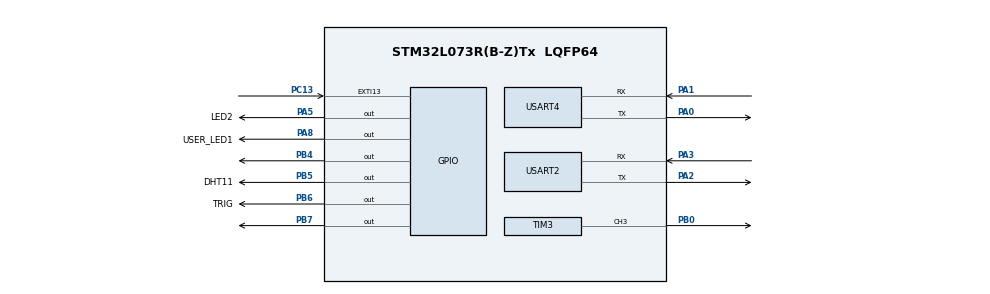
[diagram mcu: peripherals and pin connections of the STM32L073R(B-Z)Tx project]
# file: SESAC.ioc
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Mcu.Family=STM32L0
Mcu.Name=STM32L073R(B-Z)Tx
Mcu.Package=LQFP64
NVIC.EXTI4_15_IRQn=true\:0\:0\:false\:false\:true\:true\:true\:true
NVIC.TIM7_IRQn=true\:0\:0\:false\:false\:true\:true\:true\:true
NVIC.USART2_IRQn=true\:0\:0\:false\:false\:true\:true\:true\:true
NVIC.USART4_5_IRQn=true\:0\:0\:false\:false\:true\:true\:true\:true
PA0.Mode=Asynchronous
PA0.Signal=USART4_TX
PA1.Mode=Asynchronous
PA1.Signal=USART4_RX
PA13.GPIO_Label=TMS
PA13.Mode=Serial_Wire
PA13.Signal=SYS_SWDIO
PA14.GPIO_Label=TCK
PA14.Mode=Serial_Wire
PA14.Signal=SYS_SWCLK
PA2.Mode=Asynchronous
PA2.Signal=USART2_TX
PA3.Mode=Asynchronous
PA3.Signal=USART2_RX
PA5.GPIO_Label=LED2
PA5.Signal=GPIO_Output
PA8.GPIO_Label=USER_LED1
PA8.Signal=GPIO_Output
PB0.Signal=S_TIM3_CH3
PB4.Signal=GPIO_Output
PB5.GPIO_Label=DHT11
PB5.GPIO_Speed=GPIO_SPEED_FREQ_VERY_HIGH
PB5.Signal=GPIO_Output
PB6.GPIO_Label=TRIG
PB6.Signal=GPIO_Output
PB7.Signal=GPIO_Output
PC13.GPIO_ModeDefaultEXTI=GPIO_MODE_IT_FALLING
PC13.GPIO_PuPd=GPIO_PULLUP
PC13.Signal=GPXTI13
PC14-OSC32_IN.Mode=LSE-External-Oscillator
PC14-OSC32_IN.Signal=RCC_OSC32_IN
PC15-OSC32_OUT.Mode=LSE-External-Oscillator
PC15-OSC32_OUT.Signal=RCC_OSC32_OUT
PH0-OSC_IN.GPIO_Label=MCO
PH0-OSC_IN.Mode=HSE-External-Clock-Source
PH0-OSC_IN.Signal=RCC_OSC_IN
ProjectManager.HeapSize=0x200
ProjectManager.StackSize=0x400
ProjectManager.TargetToolchain=MDK-ARM V5.32
RCC.AHBFreq_Value=2097000
RCC.APB1Freq_Value=2097000
RCC.APB1TimFreq_Value=2097000
RCC.APB2Freq_Value=2097000
RCC.APB2TimFreq_Value=2097000
RCC.HSE_VALUE=8000000
RCC.HSI16_VALUE=16000000
RCC.HSI48_VALUE=48000000
RCC.HSI_VALUE=16000000
RCC.MSI_VALUE=2097000
RCC.SYSCLKFreq_VALUE=2097000
RCC.VCOOutputFreq_Value=48000000
SH.S_TIM3_CH3.0=TIM3_CH3,PWM Generation3 CH3
TIM3.Channel-PWM\ Generation3\ CH3=TIM_CHANNEL_3
TIM3.Period=1000-1
TIM3.Prescaler=8-1
USART2.VirtualMode-Asynchronous=VM_ASYNC
USART4.VirtualMode-Asynchronous=VM_ASYNC
VP_TIM7_VS_ClockSourceINT.Mode=Enable_Timer
board=NUCLEO-L073RZ

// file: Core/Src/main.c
#include "main.h"

TIM_HandleTypeDef htim3;
TIM_HandleTypeDef htim7;

UART_HandleTypeDef huart2;
UART_HandleTypeDef huart4;

/* USER CODE BEGIN PV */
uint8_t my_fault = 0;        // ? ??: 0 ??, 1 ??
uint8_t peer_fault = 0;      // ?? Fault ??
uint8_t peer_near = 0;  //distance

uint8_t txByte = 0x00;       // ?? ?? ???
uint8_t rxByte = 0x00;       // ????? ?? ???

uint32_t lastBtnTick = 0;    // ?????

uint8_t is_braking = 0;
uint8_t lastBothFault = 0;

static uint8_t brakeDone = 0;   // 0?? ?? ???? ??, 1?? ???? ?? ??
static uint8_t checkDist = 0;
/* USER CODE END PV */

void SystemClock_Config(void);
static void MX_GPIO_Init(void);
static void MX_TIM7_Init(void);
static void MX_TIM3_Init(void);
static void MX_USART2_UART_Init(void);
static void MX_USART4_UART_Init(void);

/* USER CODE BEGIN 0 */

static void UpdateFaultLeds(void)
{
  static uint32_t lastBlinkTick = 0;
  static uint8_t  blinkState = 0;

  // (1) ? ? Fault?: ?? 1? ??, ?? OFF
  if (my_fault && peer_fault)
  {
    HAL_GPIO_WritePin(GPIOB, GPIO_PIN_7, GPIO_PIN_RESET); // GREEN OFF

    if (HAL_GetTick() - lastBlinkTick >= 1000)   // 1??? ??
    {
      lastBlinkTick = HAL_GetTick();
      blinkState ^= 1;
    }

		HAL_GPIO_WritePin(GPIOA, USER_LED1_Pin,
													blinkState ? GPIO_PIN_SET : GPIO_PIN_RESET);
    return;
  }

  // (2) ? ?: ?? ?? ??(?? ???? ??? ?? ???? ? ??)
  blinkState = 0;
  lastBlinkTick = HAL_GetTick();

  // ?? OFF
  HAL_GPIO_WritePin(GPIOB, GPIO_PIN_7, GPIO_PIN_RESET);
  HAL_GPIO_WritePin(GPIOA, USER_LED1_Pin, GPIO_PIN_RESET);

  // (3) ? fault? ???: ? ?? ON
	if(my_fault==0)
	{
		HAL_GPIO_WritePin(GPIOB, GPIO_PIN_7, GPIO_PIN_SET);

	}
  if (my_fault)
  {
    HAL_GPIO_WritePin(GPIOA, USER_LED1_Pin, GPIO_PIN_SET);
		HAL_GPIO_WritePin(GPIOB, GPIO_PIN_7, GPIO_PIN_RESET);
  }
  // (4) ?? fault? ???: ? ?? ON
  else if (peer_fault)
  {
    HAL_GPIO_WritePin(GPIOB, GPIO_PIN_7, GPIO_PIN_SET);
  }
}

/* USER CODE END 0 */

int main(void)
{
  HAL_Init();

  SystemClock_Config();

  MX_GPIO_Init();
  MX_TIM7_Init();
  MX_TIM3_Init();
  MX_USART2_UART_Init();
  MX_USART4_UART_Init();
  /* USER CODE BEGIN 2 */
	HAL_TIM_PWM_Start(&htim3, TIM_CHANNEL_3);   // ? ?? ??: TIM3_CH3 = PB0 ?? ??
	//__HAL_TIM_SET_COMPARE(&htim3, TIM_CHANNEL_3, 74);
  /* USER CODE END 2 */
	HAL_UART_Receive_IT(&huart4, &rxByte, 1);
	UpdateFaultLeds();
  /* Infinite loop */
  /* USER CODE BEGIN WHILE */
	__HAL_TIM_SetCompare(&htim3, TIM_CHANNEL_3, 1500);
  while (1)
  {
    static uint32_t lastTx = 0;
		if (HAL_GetTick() - lastTx >= 100) {
			lastTx = HAL_GetTick();
			txByte = my_fault ? 0x01 : 0x00;
			HAL_UART_Transmit(&huart4, &txByte, 1, 10);
		}

		UpdateFaultLeds();

		if(peer_near){
			if(!checkDist){
				__HAL_TIM_SET_COMPARE(&htim3, TIM_CHANNEL_3, 1600);
				HAL_Delay(250); // ??? ??? ??
				__HAL_TIM_SET_COMPARE(&htim3, TIM_CHANNEL_3, 1500);
				checkDist = 1;
			}
		}
		else{
			if(checkDist){
			__HAL_TIM_SET_COMPARE(&htim3, TIM_CHANNEL_3, 1400);
				HAL_Delay(250);
				__HAL_TIM_SET_COMPARE(&htim3, TIM_CHANNEL_3, 1500);
				checkDist = 0;
			}
		}

		static uint32_t bothFaultSince = 0;
		static uint8_t  bothFaultStable = 0;
		uint8_t bothFaultNow = (my_fault && peer_fault);

		if (bothFaultNow && !brakeDone) {
				// fault? ?? ??? ?? -> ???? 1?
				__HAL_TIM_SET_COMPARE(&htim3, TIM_CHANNEL_3, 1600);
				HAL_Delay(250); // ??? ??? ??
				__HAL_TIM_SET_COMPARE(&htim3, TIM_CHANNEL_3, 1500); // (??) PWM ??
				brakeDone = 1;
		}
		else if (!bothFaultNow && brakeDone) {
				// fault? ?? ?? -> ??? 1?

				__HAL_TIM_SET_COMPARE(&htim3, TIM_CHANNEL_3, 1400);
				HAL_Delay(250);
				__HAL_TIM_SET_COMPARE(&htim3, TIM_CHANNEL_3, 1500); // (??) PWM ??
				brakeDone = 0;
		}
		HAL_Delay(10);
  }
  /* USER CODE END 3 */
}

/* USER CODE BEGIN 4 */

void HAL_UART_RxCpltCallback(UART_HandleTypeDef *huart)
{
  if (huart->Instance == USART4)
  {
		HAL_GPIO_TogglePin(GPIOA, LED2_Pin);
    // ??? ?? 0x00/0x01? peer_fault? ??
    if (rxByte == 0x00)      peer_fault = 0;
    else if (rxByte == 0x01) peer_fault = 1;

		peer_near = (rxByte & 0x02) ? 1 : 0; // ??? ????? ?? LCD/LED? ??

    UpdateFaultLeds(); // ? ??: ?? LED ??

    // ?? ?? ?? (??)
    HAL_UART_Receive_IT(&huart4, &rxByte, 1);
  }
}

void HAL_GPIO_EXTI_Callback(uint16_t GPIO_Pin)
{
  if (GPIO_Pin == GPIO_PIN_13)
  {
    uint32_t now = HAL_GetTick();
    if (now - lastBtnTick < 200) return;
    lastBtnTick = now;

    // ? fault ??
    my_fault ^= 1;

    // ???? 1??? ??: 0x00(??), 0x01(FAULT)
    txByte = (my_fault == 0) ? 0x00 : 0x01;

    // ??
    HAL_UART_Transmit(&huart4, &txByte, 1, 10);

    UpdateFaultLeds(); // ? ??: ? LED ?? ??
  }
}
/* USER CODE END 4 */

void SystemClock_Config(void)
{
  RCC_OscInitTypeDef RCC_OscInitStruct = {0};
  RCC_ClkInitTypeDef RCC_ClkInitStruct = {0};
  RCC_PeriphCLKInitTypeDef PeriphClkInit = {0};

  /** Configure the main internal regulator output voltage
  */
  __HAL_PWR_VOLTAGESCALING_CONFIG(PWR_REGULATOR_VOLTAGE_SCALE1);

  /** Initializes the RCC Oscillators according to the specified parameters
  * in the RCC_OscInitTypeDef structure.
  */
  RCC_OscInitStruct.OscillatorType = RCC_OSCILLATORTYPE_HSE;
  RCC_OscInitStruct.HSEState = RCC_HSE_BYPASS;
  RCC_OscInitStruct.PLL.PLLState = RCC_PLL_ON;
  RCC_OscInitStruct.PLL.PLLSource = RCC_PLLSOURCE_HSE;
  RCC_OscInitStruct.PLL.PLLMUL = RCC_PLLMUL_8;
  RCC_OscInitStruct.PLL.PLLDIV = RCC_PLLDIV_2;
  if (HAL_RCC_OscConfig(&RCC_OscInitStruct) != HAL_OK)
  {
    Error_Handler();
  }

  /** Initializes the CPU, AHB and APB buses clocks
  */
  RCC_ClkInitStruct.ClockType = RCC_CLOCKTYPE_HCLK|RCC_CLOCKTYPE_SYSCLK
                              |RCC_CLOCKTYPE_PCLK1|RCC_CLOCKTYPE_PCLK2;
  RCC_ClkInitStruct.SYSCLKSource = RCC_SYSCLKSOURCE_PLLCLK;

  RCC_ClkInitStruct.AHBCLKDivider = RCC_SYSCLK_DIV1;
  RCC_ClkInitStruct.APB1CLKDivider = RCC_HCLK_DIV1;
  RCC_ClkInitStruct.APB2CLKDivider = RCC_HCLK_DIV1;

  if (HAL_RCC_ClockConfig(&RCC_ClkInitStruct, FLASH_LATENCY_1) != HAL_OK)
  {
    Error_Handler();
  }
  PeriphClkInit.PeriphClockSelection = RCC_PERIPHCLK_USART2;
  PeriphClkInit.Usart2ClockSelection = RCC_USART2CLKSOURCE_PCLK1;
  if (HAL_RCCEx_PeriphCLKConfig(&PeriphClkInit) != HAL_OK)
  {
    Error_Handler();
  }
}

static void MX_TIM3_Init(void)
{

  TIM_MasterConfigTypeDef sMasterConfig = {0};
  TIM_OC_InitTypeDef sConfigOC = {0};

  htim3.Instance = TIM3;
  htim3.Init.Prescaler = 32-1;
  htim3.Init.CounterMode = TIM_COUNTERMODE_UP;
  htim3.Init.Period = 20000-1;
  htim3.Init.ClockDivision = TIM_CLOCKDIVISION_DIV1;
  htim3.Init.AutoReloadPreload = TIM_AUTORELOAD_PRELOAD_DISABLE;
  if (HAL_TIM_PWM_Init(&htim3) != HAL_OK)
  {
    Error_Handler();
  }
  sMasterConfig.MasterOutputTrigger = TIM_TRGO_RESET;
  sMasterConfig.MasterSlaveMode = TIM_MASTERSLAVEMODE_DISABLE;
  if (HAL_TIMEx_MasterConfigSynchronization(&htim3, &sMasterConfig) != HAL_OK)
  {
    Error_Handler();
  }
  sConfigOC.OCMode = TIM_OCMODE_PWM1;
  sConfigOC.Pulse = 0;
  sConfigOC.OCPolarity = TIM_OCPOLARITY_HIGH;
  sConfigOC.OCFastMode = TIM_OCFAST_DISABLE;
  if (HAL_TIM_PWM_ConfigChannel(&htim3, &sConfigOC, TIM_CHANNEL_3) != HAL_OK)
  {
    Error_Handler();
  }
  HAL_TIM_MspPostInit(&htim3);

}

static void MX_TIM7_Init(void)
{

  TIM_MasterConfigTypeDef sMasterConfig = {0};

  htim7.Instance = TIM7;
  htim7.Init.Prescaler = 0;
  htim7.Init.CounterMode = TIM_COUNTERMODE_UP;
  htim7.Init.Period = 65535;
  htim7.Init.AutoReloadPreload = TIM_AUTORELOAD_PRELOAD_DISABLE;
  if (HAL_TIM_Base_Init(&htim7) != HAL_OK)
  {
    Error_Handler();
  }
  sMasterConfig.MasterOutputTrigger = TIM_TRGO_RESET;
  sMasterConfig.MasterSlaveMode = TIM_MASTERSLAVEMODE_DISABLE;
  if (HAL_TIMEx_MasterConfigSynchronization(&htim7, &sMasterConfig) != HAL_OK)
  {
    Error_Handler();
  }

}

static void MX_USART2_UART_Init(void)
{

  huart2.Instance = USART2;
  huart2.Init.BaudRate = 115200;
  huart2.Init.WordLength = UART_WORDLENGTH_8B;
  huart2.Init.StopBits = UART_STOPBITS_1;
  huart2.Init.Parity = UART_PARITY_NONE;
  huart2.Init.Mode = UART_MODE_TX_RX;
  huart2.Init.HwFlowCtl = UART_HWCONTROL_NONE;
  huart2.Init.OverSampling = UART_OVERSAMPLING_16;
  huart2.Init.OneBitSampling = UART_ONE_BIT_SAMPLE_DISABLE;
  huart2.AdvancedInit.AdvFeatureInit = UART_ADVFEATURE_NO_INIT;
  if (HAL_UART_Init(&huart2) != HAL_OK)
  {
    Error_Handler();
  }

}

static void MX_USART4_UART_Init(void)
{

  huart4.Instance = USART4;
  huart4.Init.BaudRate = 115200;
  huart4.Init.WordLength = UART_WORDLENGTH_8B;
  huart4.Init.StopBits = UART_STOPBITS_1;
  huart4.Init.Parity = UART_PARITY_NONE;
  huart4.Init.Mode = UART_MODE_TX_RX;
  huart4.Init.HwFlowCtl = UART_HWCONTROL_NONE;
  huart4.Init.OverSampling = UART_OVERSAMPLING_16;
  huart4.Init.OneBitSampling = UART_ONE_BIT_SAMPLE_DISABLE;
  huart4.AdvancedInit.AdvFeatureInit = UART_ADVFEATURE_NO_INIT;
  if (HAL_UART_Init(&huart4) != HAL_OK)
  {
    Error_Handler();
  }

}

static void MX_GPIO_Init(void)
{
  GPIO_InitTypeDef GPIO_InitStruct = {0};

  /* GPIO Ports Clock Enable */
  __HAL_RCC_GPIOC_CLK_ENABLE();
  __HAL_RCC_GPIOH_CLK_ENABLE();
  __HAL_RCC_GPIOA_CLK_ENABLE();
  __HAL_RCC_GPIOB_CLK_ENABLE();
	 HAL_GPIO_WritePin(GPIOA, USER_LED1_Pin, GPIO_PIN_RESET);
  HAL_GPIO_WritePin(GPIOB, GPIO_PIN_7, GPIO_PIN_RESET);

  /*Configure GPIO pin Output Level */
  HAL_GPIO_WritePin(GPIOA, LED2_Pin|USER_LED1_Pin, GPIO_PIN_RESET);

  /*Configure GPIO pin Output Level */
  HAL_GPIO_WritePin(GPIOB, GPIO_PIN_4|DHT11_Pin|TRIG_Pin|GPIO_PIN_7, GPIO_PIN_RESET);

  /*Configure GPIO pin : PC13 */
  GPIO_InitStruct.Pin = GPIO_PIN_13;
  GPIO_InitStruct.Mode = GPIO_MODE_IT_FALLING;
  GPIO_InitStruct.Pull = GPIO_PULLUP;
  HAL_GPIO_Init(GPIOC, &GPIO_InitStruct);

	 /* PA8 : RED LED */
  GPIO_InitStruct.Pin = USER_LED1_Pin;
  GPIO_InitStruct.Mode = GPIO_MODE_OUTPUT_PP;
  GPIO_InitStruct.Pull = GPIO_NOPULL;
  GPIO_InitStruct.Speed = GPIO_SPEED_FREQ_LOW;
  HAL_GPIO_Init(GPIOA, &GPIO_InitStruct);

	/*Configure GPIO pin : PA9 */
	GPIO_InitStruct.Pin = GPIO_PIN_9;
	GPIO_InitStruct.Mode = GPIO_MODE_INPUT;
	GPIO_InitStruct.Pull = GPIO_NOPULL;
	HAL_GPIO_Init(GPIOA, &GPIO_InitStruct);

	/*Configure GPIO pin : PA10 */
	GPIO_InitStruct.Pin = GPIO_PIN_10;
	GPIO_InitStruct.Mode = GPIO_MODE_OUTPUT_PP;
	GPIO_InitStruct.Pull = GPIO_NOPULL;
	GPIO_InitStruct.Speed = GPIO_SPEED_FREQ_HIGH;
	HAL_GPIO_Init(GPIOA, &GPIO_InitStruct);

  /*Configure GPIO pins : LED2_Pin USER_LED1_Pin */
  GPIO_InitStruct.Pin = LED2_Pin|USER_LED1_Pin;
  GPIO_InitStruct.Mode = GPIO_MODE_OUTPUT_PP;
  GPIO_InitStruct.Pull = GPIO_NOPULL;
  GPIO_InitStruct.Speed = GPIO_SPEED_FREQ_LOW;
  HAL_GPIO_Init(GPIOA, &GPIO_InitStruct);

  /* PB7 : GREEN LED */
  GPIO_InitStruct.Pin = GPIO_PIN_7;
  GPIO_InitStruct.Mode = GPIO_MODE_OUTPUT_PP;
  GPIO_InitStruct.Pull = GPIO_NOPULL;
  GPIO_InitStruct.Speed = GPIO_SPEED_FREQ_LOW;
  HAL_GPIO_Init(GPIOB, &GPIO_InitStruct);

	//HAL_GPIO_WritePin(GPIOB, GPIO_PIN_4, GPIO_PIN_RESET);

  /*Configure GPIO pin : DHT11_Pin */
  GPIO_InitStruct.Pin = DHT11_Pin;
  GPIO_InitStruct.Mode = GPIO_MODE_OUTPUT_PP;
  GPIO_InitStruct.Pull = GPIO_NOPULL;
  GPIO_InitStruct.Speed = GPIO_SPEED_FREQ_VERY_HIGH;
  HAL_GPIO_Init(DHT11_GPIO_Port, &GPIO_InitStruct);

  /* EXTI interrupt init*/
  HAL_NVIC_SetPriority(EXTI4_15_IRQn, 0, 0);
  HAL_NVIC_EnableIRQ(EXTI4_15_IRQn);

  /* USER CODE BEGIN MX_GPIO_Init_2 */
GPIO_InitTypeDef GPIO_InitStruct2 = {0};

// PB4, PB7 Output ??

  /* USER CODE END MX_GPIO_Init_2 */
}

void Error_Handler(void)
{
  __disable_irq();
  while (1)
  {
  }
}
